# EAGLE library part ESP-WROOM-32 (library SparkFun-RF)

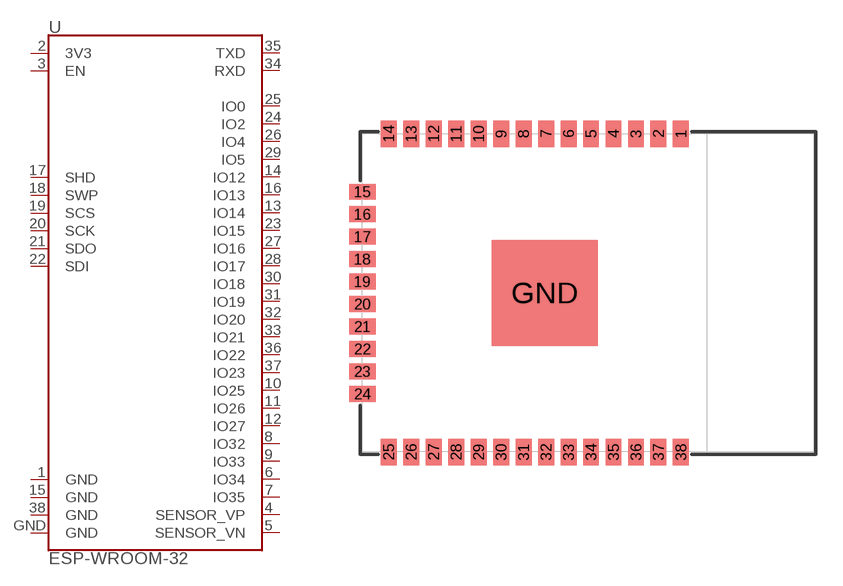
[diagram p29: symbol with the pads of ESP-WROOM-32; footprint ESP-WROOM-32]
Designator prefix U

## ESP-WROOM-32 (PROD_ID: IC-13849)  [ESP-WROOM-32]
1  GND
2  3V3
3  EN
4  SENSOR_VP
5  SENSOR_VN
6  IO34
7  IO35
8  IO32
9  IO33
10  IO25
11  IO26
12  IO27
13  IO14
14  IO12
15  GND
16  IO13
17  SHD
18  SWP
19  SCS
20  SCK
21  SDO
22  SDI
23  IO15
24  IO2
25  IO0
26  IO4
27  IO16
28  IO17
29  IO5
30  IO18
31  IO19
32  IO20
33  IO21
34  RXD
35  TXD
36  IO22
37  IO23
38  GND
GND  GND

## Footprint ESP-WROOM-32 (pad centres in mm)
smd 0.9 x 1.5: 1 7.7,9; 2 6.43,9; 3 5.16,9; 4 3.89,9; 5 2.62,9; 6 1.35,9; 7 0.08,9; 8 -1.19,9; 9 -2.46,9; 10 -3.73,9; 11 -5,9; 12 -6.27,9; 13 -7.54,9; 14 -8.81,9; 25 -8.81,-9; 26 -7.54,-9; 27 -6.27,-9; 28 -5,-9; 29 -3.73,-9; 30 -2.46,-9; 31 -1.19,-9; 32 0.08,-9; 33 1.35,-9; 34 2.62,-9; 35 3.89,-9; 36 5.16,-9; 37 6.43,-9; 38 7.7,-9
smd 1.5 x 0.9: 15 -10.3,5.715; 16 -10.3,4.445; 17 -10.3,3.175; 18 -10.3,1.905; 19 -10.3,0.635; 20 -10.3,-0.635; 21 -10.3,-1.905; 22 -10.3,-3.175; 23 -10.3,-4.445; 24 -10.3,-5.715
smd 6 x 6: GND 0,0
